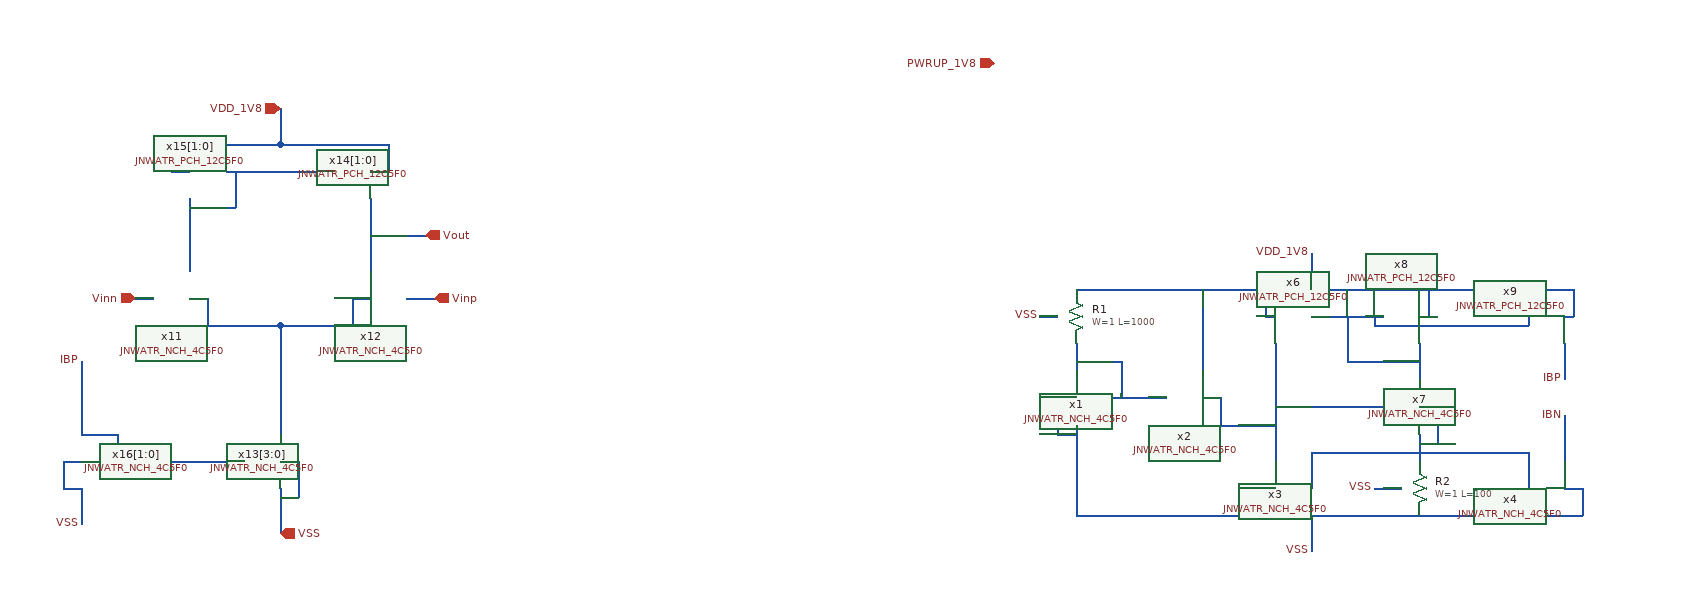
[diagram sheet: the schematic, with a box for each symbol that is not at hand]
v {xschem version=3.4.7 file_version=1.2}
G {}
K {}
V {}
S {}
E {}
P 4 1 -670 10 {}
N -720 -140 -620 -140 {lab=#net1}
N -820 -140 -720 -140 {lab=#net1}
N -720 -140 -720 -20 {lab=#net1}
N -820 -280 -820 -200 {lab=#net2}
N -780 -310 -660 -310 {lab=#net2}
N -820 -340 -720 -340 {lab=VDD_1V8}
N -720 -380 -720 -340 {lab=VDD_1V8}
N -720 -340 -620 -340 {lab=VDD_1V8}
N -640 -170 -620 -170 {lab=#net1}
N -640 -170 -640 -140 {lab=#net1}
N -820 -170 -800 -170 {lab=#net1}
N -800 -170 -800 -140 {lab=#net1}
N -840 -310 -820 -310 {lab=VDD_1V8}
N -880 -170 -860 -170 {lab=Vinn}
N -720 40 -720 80 {lab=VSS}
N -720 80 -720 90 {lab=VSS}
N -720 10 -700 10 {lab=VSS}
N -700 10 -700 50 {lab=VSS}
N -720 50 -700 50 {lab=VSS}
N -620 -280 -620 -200 {lab=Vout}
N -620 -310 -600 -310 {lab=VDD_1V8}
N -600 -340 -600 -310 {lab=VDD_1V8}
N -620 -340 -600 -340 {lab=VDD_1V8}
N -820 -280 -820 -200 {lab=#net2}
N -770 -310 -770 -270 {lab=#net2}
N -840 -340 -840 -310 {lab=VDD_1V8}
N -900 10 -760 10 {lab=IBP}
N -900 -20 -900 10 {lab=IBP}
N -940 -20 -900 -20 {lab=IBP}
N -940 40 -940 80 {lab=VSS}
N -960 10 -940 10 {lab=VSS}
N -960 10 -960 40 {lab=VSS}
N -960 40 -940 40 {lab=VSS}
N 490 40 520 40 {lab=VSS}
N 380 70 540 70 {lab=VSS}
N 540 70 700 70 {lab=VSS}
N 420 70 420 110 {lab=VSS}
N 380 -180 540 -180 {lab=VDD_1V8}
N 540 -180 700 -180 {lab=VDD_1V8}
N 380 -120 380 10 {lab=#net3}
N 420 30 420 40 {lab=#net4}
N 660 30 660 40 {lab=#net4}
N 380 -50 500 -50 {lab=#net3}
N 540 -120 540 -80 {lab=#net5}
N 420 -150 500 -150 {lab=#net5}
N 460 -150 460 -100 {lab=#net5}
N 490 -150 490 -140 {lab=#net5}
N 490 -140 660 -140 {lab=#net5}
N 660 -150 660 -140 {lab=#net5}
N 540 -20 540 10 {lab=#net4}
N 370 -150 380 -150 {lab=VDD_1V8}
N 370 -180 370 -150 {lab=VDD_1V8}
N 540 -150 550 -150 {lab=VDD_1V8}
N 550 -180 550 -150 {lab=VDD_1V8}
N 700 -150 710 -150 {lab=VDD_1V8}
N 710 -180 710 -150 {lab=VDD_1V8}
N 700 -180 710 -180 {lab=VDD_1V8}
N 700 -120 700 -80 {lab=IBP}
N 700 -40 700 10 {lab=IBN}
N 420 -220 420 -180 {lab=VDD_1V8}
N -820 -270 -770 -270 {lab=#net2}
N -840 -340 -820 -340 {lab=VDD_1V8}
N -620 -240 -560 -240 {lab=Vout}
N -940 -100 -940 -20 {lab=IBP}
N 540 -50 560 -50 {lab=#net4}
N 360 40 380 40 {lab=VSS}
N 360 40 360 70 {lab=VSS}
N 700 40 720 40 {lab=VSS}
N 720 40 720 70 {lab=VSS}
N 700 70 720 70 {lab=VSS}
N 540 -0 660 -0 {lab=#net4}
N 660 -0 660 30 {lab=#net4}
N 420 -0 420 30 {lab=#net4}
N 560 -50 560 -10 {lab=#net4}
N 540 -10 560 -10 {lab=#net4}
N 460 -100 540 -100 {lab=#net5}
N 360 70 380 70 {lab=VSS}
N 420 -0 540 -0 {lab=#net4}
N 370 -180 380 -180 {lab=VDD_1V8}
N 160 -120 160 -90 {lab=#net6}
N 160 -30 160 70 {lab=VSS}
N 300 -30 380 -30 {lab=#net3}
N 200 -60 260 -60 {lab=#net6}
N 210 -100 210 -60 {lab=#net6}
N 160 -100 210 -100 {lab=#net6}
N 160 70 360 70 {lab=VSS}
N 300 -60 320 -60 {lab=#net3}
N 320 -60 320 -30 {lab=#net3}
N 140 -60 160 -60 {lab=VSS}
N 140 -60 140 -20 {lab=VSS}
N 140 -20 160 -20 {lab=VSS}
N 160 -180 370 -180 {lab=VDD_1V8}
N 300 -180 300 -90 {lab=VDD_1V8}
N -580 -170 -550 -170 {lab=Vinp}
N 120 -150 140 -150 {lab=VSS}
C {devices/ipin.sym} -880 -170 0 0 {name=p2 lab=Vinn}
C {devices/ipin.sym} -550 -170 0 1 {name=p3 lab=Vinp}
C {devices/ipin.sym} -720 -380 0 0 {name=p5 lab=VDD_1V8}
C {devices/ipin.sym} 70 -430 0 0 {name=p6 lab=PWRUP_1V8}
C {JNW_ATR_SKY130A/JNWATR_NCH_4C5F0.sym} -860 -170 0 0 {name=x11}
C {JNW_ATR_SKY130A/JNWATR_NCH_4C5F0.sym} -580 -170 0 1 {name=x12 }
C {JNW_ATR_SKY130A/JNWATR_NCH_4C5F0.sym} -760 10 0 0 {name=x13[3:0] }
C {JNW_ATR_SKY130A/JNWATR_PCH_12C5F0.sym} -660 -310 0 0 {name=x14[1:0] }
C {JNW_ATR_SKY130A/JNWATR_PCH_12C5F0.sym} -780 -310 0 1 {name=x15[1:0] }
C {JNW_ATR_SKY130A/JNWATR_NCH_4C5F0.sym} -900 10 0 1 {name=x16[1:0] }
C {devices/lab_pin.sym} -940 80 0 0 {name=p17 sig_type=std_logic lab=VSS}
C {JNW_ATR_SKY130A/JNWATR_NCH_4C5F0.sym} 420 40 0 1 {name=x3 }
C {JNW_ATR_SKY130A/JNWATR_NCH_4C5F0.sym} 660 40 0 0 {name=x4 }
C {JNW_ATR_SKY130A/JNWATR_NCH_4C5F0.sym} 500 -50 0 0 {name=x7}
C {devices/lab_pin.sym} 490 40 0 0 {name=p1 sig_type=std_logic lab=VSS}
C {sky130_fd_pr/res_high_po.sym} 540 40 0 0 {name=R2
W=1
L=100
model=res_high_po
spiceprefix=X
mult=1}
C {devices/lab_pin.sym} 420 110 0 0 {name=p4 sig_type=std_logic lab=VSS}
C {JNW_ATR_SKY130A/JNWATR_PCH_12C5F0.sym} 500 -150 0 0 {name=x8}
C {JNW_ATR_SKY130A/JNWATR_PCH_12C5F0.sym} 660 -150 0 0 {name=x9}
C {devices/lab_pin.sym} 420 -220 0 0 {name=p7 sig_type=std_logic lab=VDD_1V8}
C {devices/opin.sym} -720 90 0 0 {name=p8 lab=VSS}
C {devices/lab_pin.sym} 700 -80 0 0 {name=p9 sig_type=std_logic lab=IBP}
C {devices/lab_pin.sym} 700 -40 0 0 {name=p10 sig_type=std_logic lab=IBN}
C {devices/opin.sym} -560 -240 0 0 {name=p11 lab=Vout}
C {devices/lab_pin.sym} -940 -100 0 0 {name=p12 sig_type=std_logic lab=IBP}
C {JNW_ATR_SKY130A/JNWATR_PCH_12C5F0.sym} 420 -150 0 1 {name=x6}
C {JNW_ATR_SKY130A/JNWATR_NCH_4C5F0.sym} 200 -60 0 1 {name=x1 }
C {JNW_ATR_SKY130A/JNWATR_NCH_4C5F0.sym} 260 -60 0 0 {name=x2 }
C {sky130_fd_pr/res_high_po.sym} 160 -150 0 0 {name=R1
W=1
L=1000
model=res_high_po
spiceprefix=X
mult=1}
C {devices/lab_pin.sym} 120 -150 0 0 {name=p13 sig_type=std_logic lab=VSS}
